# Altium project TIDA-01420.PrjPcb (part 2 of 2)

## Sheet TIDA-01420-E1_EVM_Hardware.SchDoc: Hardware
size 431 x 279 mm; Date: Not shown in title block; ApprovedBy: Not shown in title block; CheckedBy: Not shown in title block; Author: Not shown in title block; CompanyName: Not shown in title block; DrawnBy: PN; Engineer: PN; Organization: Not shown in title block; Address1: Not shown in title block; Address2: Not shown in title block; Address3: Not shown in title block; Address4: Not shown in title block; DocumentNumber: 1; Revision: Use project parameter SCH_Rev; SheetNumber: 5; SheetTotal: 5; PageSetup: Record=PageOptions¦CenterHorizontal=True¦CenterVertical=True¦PrintScale=1.00¦XCorrection=1.00¦YCorrection=1.00¦PrintKind=0¦BorderSize=5000000¦LeftOffset=0¦BottomOffset=0¦Orientation=2¦PaperLength=1000¦PaperWidth=1000¦Scale=100¦PaperSource=15¦PrintQuality=600¦MediaType=1¦DitherType=10¦PaperKind=Letter¦PrintScaleMode=1

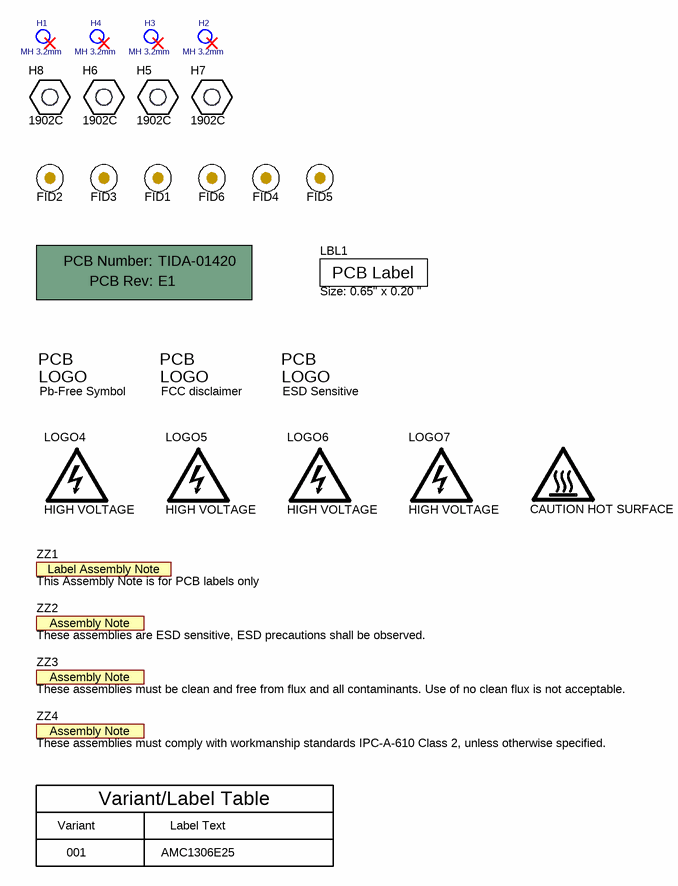
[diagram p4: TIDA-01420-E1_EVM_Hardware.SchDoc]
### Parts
!PCB1  Printed Circuit Board  (value not drawn)  (mechanical)
CAUTION_HOT_SURFACE  CAUTION HOT SURFACE  [IEC_HotSurface_Medium]  (value not drawn)  (no BOM)
ESD_Sensitive  ESD Susceptible  [ESD_Overlay_Medium]  (value not drawn)  (no BOM)
FID1  Fiducial  [Fiducial10-20]  (value not drawn)
FID2  Fiducial  [Fiducial10-20]  (value not drawn)
FID3  Fiducial  [Fiducial10-20]  (value not drawn)
FID4  Fiducial  [Fiducial10-20]  (value not drawn)
FID5  Fiducial  [Fiducial10-20]  (value not drawn)
FID6  Fiducial  [Fiducial10-20]  (value not drawn)
H1  MH 3.2mm  [MH3.2_H5_W6_KO8_STARHEAD]
H2  MH 3.2mm  [MH3.2_H5_W6_KO8_STARHEAD]
H3  MH 3.2mm  [MH3.2_H5_W6_KO8_STARHEAD]
H4  MH 3.2mm  [MH3.2_H5_W6_KO8_STARHEAD]
H5  1902C  [Keystone_1902C]
H6  1902C  [Keystone_1902C]
H7  1902C  [Keystone_1902C]
H8  1902C  [Keystone_1902C]
LBL1  Size: 0.65" x 0.20 "  [Label_650x200]
Logo2  Pb-Free Symbol  [Pb-Free_Overlay_Small]  (no BOM)
Logo3  FCC disclaimer  [FCC_disclaimer]  (no BOM)
LOGO4  HIGH VOLTAGE  [IEC_HighVoltage_medium]  (no BOM)
LOGO5  HIGH VOLTAGE  [IEC_HighVoltage_medium]  (no BOM)
LOGO6  HIGH VOLTAGE  [IEC_HighVoltage_medium]  (no BOM)
LOGO7  HIGH VOLTAGE  [IEC_HighVoltage_medium]  (no BOM)
ZZ1  This Assembly Note is for PCB labels only  [AssemblyNoteLabel]  (no BOM)
ZZ2  These assemblies are ESD sensitive, ESD precautions shall be observed.  [AssemblyNote]  (no BOM)
ZZ3  These assemblies must be clean and free from flux and all contaminants. Use of no clean flux is not acceptable.  [AssemblyNote]  (no BOM)
ZZ4  These assemblies must comply with workmanship standards IPC-A-610 Class 2, unless otherwise specified.  [AssemblyNote]  (no BOM)

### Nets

Not connected (* = marked no-connect by the designer): H1 1*; H2 1*; H3 1*; H4 1*

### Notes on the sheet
- Variant/Label Table
- Variant
- 001
- Label Text
- AMC1306E25

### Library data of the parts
!PCB1 = PCB: Manufacturer: Any; PartNumber: TIDA-01420; SymbolCreator: a0412235
CAUTION_HOT_SURFACE = IEC_HotSurface: IEC 61010-1 Hot Surface Warning; SymbolCreator: a0412235
ESD_Sensitive = ESD_Susceptible: ESD Susceptible Symbol; SymbolCreator: a0412235
FID1-FID6 = Fiducial: Fiducial mark.  There is nothing to buy or mount.; SymbolCreator: codlsc
H1-H4 = MH 3_0.5MM: Mountin hole, NPTH Drill 3.2mm
H5-H8 = 1902C: Standoff, Hex, 0.5"L #4-40 Nylon; Manufacturer: Keystone; CompType: Hardware
LBL1 = THT-14-423-10: Thermal Transfer Printable Labels, 0.650" W x 0.200" H - 10,000 per roll; Manufacturer: Brady; SymbolCreator: a0412235; CompType: Label
Logo2 = Pb-Free: SymbolCreator: a0412235
Logo3 = FCC_disclaimer: SymbolCreator: codlsc
LOGO4-LOGO7 = IEC_HighVoltage: IEC 61010-1 High Voltage Warning; SymbolCreator: a0412235
ZZ1 = AssemblyNoteLabel: SymbolCreator: a0412235
ZZ2-ZZ4 = AssemblyNote: SymbolCreator: codlsc

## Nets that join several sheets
3V3: TIDA-01420-E1_Gate drivers (21 pins), TIDA-01420-E1_IGBT Module, Temp and DC link sense (6 pins), TIDA-01420-E1_Current sense, MCU Interface (15 pins)
GND: TIDA-01420-E1_Gate drivers (41 pins), TIDA-01420-E1_IGBT Module, Temp and DC link sense (6 pins), TIDA-01420-E1_Current sense, MCU Interface (27 pins)
GND_UT: TIDA-01420-E1_Gate drivers (7 pins), TIDA-01420-E1_IGBT Module, Temp and DC link sense (C74.2 R112.1 TP18.1 U24.10), TIDA-01420-E1_Current sense, MCU Interface (5 pins)
GND_VT: TIDA-01420-E1_Gate drivers (7 pins), TIDA-01420-E1_IGBT Module, Temp and DC link sense (C73.2 R32.1 TP16.1 U24.6)
GND_WT: TIDA-01420-E1_Gate drivers (7 pins), TIDA-01420-E1_IGBT Module, Temp and DC link sense (5 pins), TIDA-01420-E1_Current sense, MCU Interface (5 pins)
VCC: TIDA-01420-E1_Gate drivers (19 pins), TIDA-01420-E1_IGBT Module, Temp and DC link sense (R110.1)
VCC_UT: TIDA-01420-E1_Gate drivers (6 pins), TIDA-01420-E1_Current sense, MCU Interface (C21.2 U22.2)
VCC_WT: TIDA-01420-E1_Gate drivers (6 pins), TIDA-01420-E1_Current sense, MCU Interface (C71.2 U20.2)
VDC-: TIDA-01420-E1_Gate drivers (22 pins), TIDA-01420-E1_IGBT Module, Temp and DC link sense (44 pins)
BRAKE_IGBT_GATE: TIDA-01420-E1_Gate drivers (R71.2 R94.2), TIDA-01420-E1_IGBT Module, Temp and DC link sense (C78.1 Q1.1 R96.2)
MCLK: TIDA-01420-E1_IGBT Module, Temp and DC link sense (R55.2 R58.2 TP2.1 TP15.1), TIDA-01420-E1_Current sense, MCU Interface (5 pins)
MDATA_TMP: TIDA-01420-E1_IGBT Module, Temp and DC link sense (R59.2 TP3.1), TIDA-01420-E1_Current sense, MCU Interface (J1.24)
MDATA_VDC: TIDA-01420-E1_IGBT Module, Temp and DC link sense (R56.2 TP1.1), TIDA-01420-E1_Current sense, MCU Interface (J1.23)
PWM_BRAKE+: TIDA-01420-E1_Gate drivers (R8.2), TIDA-01420-E1_Current sense, MCU Interface (J1.8)
PWM_UB+: TIDA-01420-E1_Gate drivers (R144.2), TIDA-01420-E1_Current sense, MCU Interface (J1.2)
PWM_UT+: TIDA-01420-E1_Gate drivers (R143.2), TIDA-01420-E1_Current sense, MCU Interface (J1.3)
PWM_VB+: TIDA-01420-E1_Gate drivers (R141.2), TIDA-01420-E1_Current sense, MCU Interface (J1.4)
PWM_VT+: TIDA-01420-E1_Gate drivers (R142.2), TIDA-01420-E1_Current sense, MCU Interface (J1.5)
PWM_WB+: TIDA-01420-E1_Gate drivers (R139.2), TIDA-01420-E1_Current sense, MCU Interface (J1.6)
PWM_WT+: TIDA-01420-E1_Gate drivers (R140.2), TIDA-01420-E1_Current sense, MCU Interface (J1.7)
U_BOT: TIDA-01420-E1_Gate drivers (R23.2 R25.2 R27.2), TIDA-01420-E1_IGBT Module, Temp and DC link sense (C75.1 R12.2 TP19.1 U24.11)
U_PHASE: TIDA-01420-E1_IGBT Module, Temp and DC link sense (J4.1 R120.2), TIDA-01420-E1_Current sense, MCU Interface (R80.1)
U_PHASE_REF: TIDA-01420-E1_IGBT Module, Temp and DC link sense (5 pins), TIDA-01420-E1_Current sense, MCU Interface (R79.1)
U_TOP: TIDA-01420-E1_Gate drivers (R15.2 R18.2 R21.2), TIDA-01420-E1_IGBT Module, Temp and DC link sense (C74.1 R112.2 TP17.1 U24.9)
V_BOT: TIDA-01420-E1_Gate drivers (R35.2 R37.2 R39.2), TIDA-01420-E1_IGBT Module, Temp and DC link sense (C76.1 R38.2 TP21.1 U24.7)
V_TOP: TIDA-01420-E1_Gate drivers (R29.2 R31.2 R33.2), TIDA-01420-E1_IGBT Module, Temp and DC link sense (C73.1 R32.2 TP14.1 U24.5)
W_BOT: TIDA-01420-E1_Gate drivers (R9.2 R11.2 R13.2), TIDA-01420-E1_IGBT Module, Temp and DC link sense (C77.1 R26.2 TP23.1 U24.3)
W_PHASE: TIDA-01420-E1_IGBT Module, Temp and DC link sense (J4.3 R118.2), TIDA-01420-E1_Current sense, MCU Interface (R86.1)
W_PHASE_REF: TIDA-01420-E1_IGBT Module, Temp and DC link sense (6 pins), TIDA-01420-E1_Current sense, MCU Interface (R85.1)
W_TOP: TIDA-01420-E1_Gate drivers (R3.2 R17.2 R19.2), TIDA-01420-E1_IGBT Module, Temp and DC link sense (C72.1 R20.2 TP12.1 U24.1)

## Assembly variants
001: not fitted C9 C10 C11 C12 C13 C15 C16 C18 C19 C20 C22 C28 C29 C31 C37 C38 C39 C43 C44 C45 C48 C49 C50 C51 C52 C53 C54 C56 C57 C72 C73 C74 C75 C76 C77 C78 C81 C83 C84 C92 C94 D2 D3 D4 D5 D6 D7 D9 D10 D11 J3 J5 J6 J13 Q1 R2 R5 R8 R11 R14 R17 R18 R22 R25 R28 R31 R34 R37 R40 R71 R81 R90 R94 R96 R99 R100 R101 R102 R103 R105 R168 R169 R170 R171 R172 R173 U10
